VERSION 5.4 ;
NAMESCASESENSITIVE ON ;
BUSBITCHARS "[]" ;
DIVIDERCHAR "/" ;
UNITS
  DATABASE MICRONS 2000 ;
END UNITS
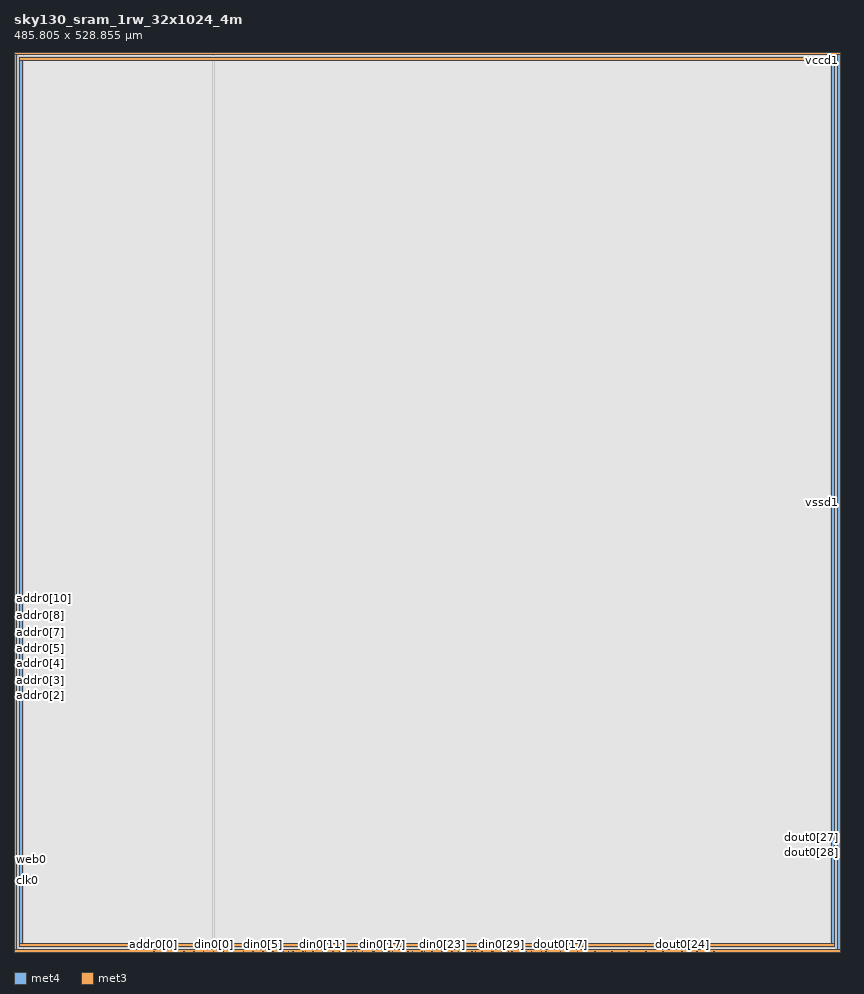
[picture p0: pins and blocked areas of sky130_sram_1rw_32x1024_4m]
MACRO sky130_sram_1rw_32x1024_4m
   CLASS BLOCK ;
   SIZE 485.805 BY 528.855 ;
   SYMMETRY X Y R90 ;
   PIN din0[0]
      DIRECTION INPUT ;
      PORT
         LAYER met4 ;
         RECT  117.08 0.0 117.46 0.38 ;
      END
   END din0[0]
   PIN din0[1]
      DIRECTION INPUT ;
      PORT
         LAYER met4 ;
         RECT  122.92 0.0 123.3 0.38 ;
      END
   END din0[1]
   PIN din0[2]
      DIRECTION INPUT ;
      PORT
         LAYER met4 ;
         RECT  128.76 0.0 129.14 0.38 ;
      END
   END din0[2]
   PIN din0[3]
      DIRECTION INPUT ;
      PORT
         LAYER met4 ;
         RECT  134.6 0.0 134.98 0.38 ;
      END
   END din0[3]
   PIN din0[4]
      DIRECTION INPUT ;
      PORT
         LAYER met4 ;
         RECT  140.44 0.0 140.82 0.38 ;
      END
   END din0[4]
   PIN din0[5]
      DIRECTION INPUT ;
      PORT
         LAYER met4 ;
         RECT  146.28 0.0 146.66 0.38 ;
      END
   END din0[5]
   PIN din0[6]
      DIRECTION INPUT ;
      PORT
         LAYER met4 ;
         RECT  152.12 0.0 152.5 0.38 ;
      END
   END din0[6]
   PIN din0[7]
      DIRECTION INPUT ;
      PORT
         LAYER met4 ;
         RECT  157.96 0.0 158.34 0.38 ;
      END
   END din0[7]
   PIN din0[8]
      DIRECTION INPUT ;
      PORT
         LAYER met4 ;
         RECT  163.8 0.0 164.18 0.38 ;
      END
   END din0[8]
   PIN din0[9]
      DIRECTION INPUT ;
      PORT
         LAYER met4 ;
         RECT  169.64 0.0 170.02 0.38 ;
      END
   END din0[9]
   PIN din0[10]
      DIRECTION INPUT ;
      PORT
         LAYER met4 ;
         RECT  175.48 0.0 175.86 0.38 ;
      END
   END din0[10]
   PIN din0[11]
      DIRECTION INPUT ;
      PORT
         LAYER met4 ;
         RECT  181.32 0.0 181.7 0.38 ;
      END
   END din0[11]
   PIN din0[12]
      DIRECTION INPUT ;
      PORT
         LAYER met4 ;
         RECT  187.16 0.0 187.54 0.38 ;
      END
   END din0[12]
   PIN din0[13]
      DIRECTION INPUT ;
      PORT
         LAYER met4 ;
         RECT  193.0 0.0 193.38 0.38 ;
      END
   END din0[13]
   PIN din0[14]
      DIRECTION INPUT ;
      PORT
         LAYER met4 ;
         RECT  198.84 0.0 199.22 0.38 ;
      END
   END din0[14]
   PIN din0[15]
      DIRECTION INPUT ;
      PORT
         LAYER met4 ;
         RECT  204.68 0.0 205.06 0.38 ;
      END
   END din0[15]
   PIN din0[16]
      DIRECTION INPUT ;
      PORT
         LAYER met4 ;
         RECT  210.52 0.0 210.9 0.38 ;
      END
   END din0[16]
   PIN din0[17]
      DIRECTION INPUT ;
      PORT
         LAYER met4 ;
         RECT  216.36 0.0 216.74 0.38 ;
      END
   END din0[17]
   PIN din0[18]
      DIRECTION INPUT ;
      PORT
         LAYER met4 ;
         RECT  222.2 0.0 222.58 0.38 ;
      END
   END din0[18]
   PIN din0[19]
      DIRECTION INPUT ;
      PORT
         LAYER met4 ;
         RECT  228.04 0.0 228.42 0.38 ;
      END
   END din0[19]
   PIN din0[20]
      DIRECTION INPUT ;
      PORT
         LAYER met4 ;
         RECT  233.88 0.0 234.26 0.38 ;
      END
   END din0[20]
   PIN din0[21]
      DIRECTION INPUT ;
      PORT
         LAYER met4 ;
         RECT  239.72 0.0 240.1 0.38 ;
      END
   END din0[21]
   PIN din0[22]
      DIRECTION INPUT ;
      PORT
         LAYER met4 ;
         RECT  245.56 0.0 245.94 0.38 ;
      END
   END din0[22]
   PIN din0[23]
      DIRECTION INPUT ;
      PORT
         LAYER met4 ;
         RECT  251.4 0.0 251.78 0.38 ;
      END
   END din0[23]
   PIN din0[24]
      DIRECTION INPUT ;
      PORT
         LAYER met4 ;
         RECT  257.24 0.0 257.62 0.38 ;
      END
   END din0[24]
   PIN din0[25]
      DIRECTION INPUT ;
      PORT
         LAYER met4 ;
         RECT  263.08 0.0 263.46 0.38 ;
      END
   END din0[25]
   PIN din0[26]
      DIRECTION INPUT ;
      PORT
         LAYER met4 ;
         RECT  268.92 0.0 269.3 0.38 ;
      END
   END din0[26]
   PIN din0[27]
      DIRECTION INPUT ;
      PORT
         LAYER met4 ;
         RECT  274.76 0.0 275.14 0.38 ;
      END
   END din0[27]
   PIN din0[28]
      DIRECTION INPUT ;
      PORT
         LAYER met4 ;
         RECT  280.6 0.0 280.98 0.38 ;
      END
   END din0[28]
   PIN din0[29]
      DIRECTION INPUT ;
      PORT
         LAYER met4 ;
         RECT  286.44 0.0 286.82 0.38 ;
      END
   END din0[29]
   PIN din0[30]
      DIRECTION INPUT ;
      PORT
         LAYER met4 ;
         RECT  292.28 0.0 292.66 0.38 ;
      END
   END din0[30]
   PIN din0[31]
      DIRECTION INPUT ;
      PORT
         LAYER met4 ;
         RECT  298.12 0.0 298.5 0.38 ;
      END
   END din0[31]
   PIN din0[32]
      DIRECTION INPUT ;
      PORT
         LAYER met4 ;
         RECT  303.96 0.0 304.34 0.38 ;
      END
   END din0[32]
   PIN addr0[0]
      DIRECTION INPUT ;
      PORT
         LAYER met4 ;
         RECT  82.04 0.0 82.42 0.38 ;
      END
   END addr0[0]
   PIN addr0[1]
      DIRECTION INPUT ;
      PORT
         LAYER met4 ;
         RECT  87.88 0.0 88.26 0.38 ;
      END
   END addr0[1]
   PIN addr0[2]
      DIRECTION INPUT ;
      PORT
         LAYER met3 ;
         RECT  0.0 150.77 0.38 151.15 ;
      END
   END addr0[2]
   PIN addr0[3]
      DIRECTION INPUT ;
      PORT
         LAYER met3 ;
         RECT  0.0 159.27 0.38 159.65 ;
      END
   END addr0[3]
   PIN addr0[4]
      DIRECTION INPUT ;
      PORT
         LAYER met3 ;
         RECT  0.0 164.91 0.38 165.29 ;
      END
   END addr0[4]
   PIN addr0[5]
      DIRECTION INPUT ;
      PORT
         LAYER met3 ;
         RECT  0.0 173.41 0.38 173.79 ;
      END
   END addr0[5]
   PIN addr0[6]
      DIRECTION INPUT ;
      PORT
         LAYER met3 ;
         RECT  0.0 179.05 0.38 179.43 ;
      END
   END addr0[6]
   PIN addr0[7]
      DIRECTION INPUT ;
      PORT
         LAYER met3 ;
         RECT  0.0 187.55 0.38 187.93 ;
      END
   END addr0[7]
   PIN addr0[8]
      DIRECTION INPUT ;
      PORT
         LAYER met3 ;
         RECT  0.0 193.19 0.38 193.57 ;
      END
   END addr0[8]
   PIN addr0[9]
      DIRECTION INPUT ;
      PORT
         LAYER met3 ;
         RECT  0.0 201.69 0.38 202.07 ;
      END
   END addr0[9]
   PIN addr0[10]
      DIRECTION INPUT ;
      PORT
         LAYER met3 ;
         RECT  0.0 207.33 0.38 207.71 ;
      END
   END addr0[10]
   PIN csb0
      DIRECTION INPUT ;
      PORT
         LAYER met3 ;
         RECT  0.0 41.11 0.38 41.49 ;
      END
   END csb0
   PIN web0
      DIRECTION INPUT ;
      PORT
         LAYER met3 ;
         RECT  0.0 49.61 0.38 49.99 ;
      END
   END web0
   PIN clk0
      DIRECTION INPUT ;
      PORT
         LAYER met3 ;
         RECT  0.0 41.855 0.38 42.235 ;
      END
   END clk0
   PIN wmask0[0]
      DIRECTION INPUT ;
      PORT
         LAYER met4 ;
         RECT  93.72 0.0 94.1 0.38 ;
      END
   END wmask0[0]
   PIN wmask0[1]
      DIRECTION INPUT ;
      PORT
         LAYER met4 ;
         RECT  99.56 0.0 99.94 0.38 ;
      END
   END wmask0[1]
   PIN wmask0[2]
      DIRECTION INPUT ;
      PORT
         LAYER met4 ;
         RECT  105.4 0.0 105.78 0.38 ;
      END
   END wmask0[2]
   PIN wmask0[3]
      DIRECTION INPUT ;
      PORT
         LAYER met4 ;
         RECT  111.24 0.0 111.62 0.38 ;
      END
   END wmask0[3]
   PIN spare_wen0
      DIRECTION INPUT ;
      PORT
         LAYER met4 ;
         RECT  309.8 0.0 310.18 0.38 ;
      END
   END spare_wen0
   PIN dout0[0]
      DIRECTION OUTPUT ;
      PORT
         LAYER met4 ;
         RECT  149.765 0.0 150.145 0.38 ;
      END
   END dout0[0]
   PIN dout0[1]
      DIRECTION OUTPUT ;
      PORT
         LAYER met4 ;
         RECT  161.03 0.0 161.41 0.38 ;
      END
   END dout0[1]
   PIN dout0[2]
      DIRECTION OUTPUT ;
      PORT
         LAYER met4 ;
         RECT  171.03 0.0 171.41 0.38 ;
      END
   END dout0[2]
   PIN dout0[3]
      DIRECTION OUTPUT ;
      PORT
         LAYER met4 ;
         RECT  182.41 0.0 182.79 0.38 ;
      END
   END dout0[3]
   PIN dout0[4]
      DIRECTION OUTPUT ;
      PORT
         LAYER met4 ;
         RECT  191.03 0.0 191.41 0.38 ;
      END
   END dout0[4]
   PIN dout0[5]
      DIRECTION OUTPUT ;
      PORT
         LAYER met4 ;
         RECT  201.03 0.0 201.41 0.38 ;
      END
   END dout0[5]
   PIN dout0[6]
      DIRECTION OUTPUT ;
      PORT
         LAYER met4 ;
         RECT  211.21 0.0 211.59 0.38 ;
      END
   END dout0[6]
   PIN dout0[7]
      DIRECTION OUTPUT ;
      PORT
         LAYER met4 ;
         RECT  220.345 0.0 220.725 0.38 ;
      END
   END dout0[7]
   PIN dout0[8]
      DIRECTION OUTPUT ;
      PORT
         LAYER met4 ;
         RECT  231.285 0.0 231.665 0.38 ;
      END
   END dout0[8]
   PIN dout0[9]
      DIRECTION OUTPUT ;
      PORT
         LAYER met4 ;
         RECT  241.03 0.0 241.41 0.38 ;
      END
   END dout0[9]
   PIN dout0[10]
      DIRECTION OUTPUT ;
      PORT
         LAYER met4 ;
         RECT  252.41 0.0 252.79 0.38 ;
      END
   END dout0[10]
   PIN dout0[11]
      DIRECTION OUTPUT ;
      PORT
         LAYER met4 ;
         RECT  261.03 0.0 261.41 0.38 ;
      END
   END dout0[11]
   PIN dout0[12]
      DIRECTION OUTPUT ;
      PORT
         LAYER met4 ;
         RECT  271.03 0.0 271.41 0.38 ;
      END
   END dout0[12]
   PIN dout0[13]
      DIRECTION OUTPUT ;
      PORT
         LAYER met4 ;
         RECT  281.29 0.0 281.67 0.38 ;
      END
   END dout0[13]
   PIN dout0[14]
      DIRECTION OUTPUT ;
      PORT
         LAYER met4 ;
         RECT  290.345 0.0 290.725 0.38 ;
      END
   END dout0[14]
   PIN dout0[15]
      DIRECTION OUTPUT ;
      PORT
         LAYER met4 ;
         RECT  301.03 0.0 301.41 0.38 ;
      END
   END dout0[15]
   PIN dout0[16]
      DIRECTION OUTPUT ;
      PORT
         LAYER met4 ;
         RECT  312.41 0.0 312.79 0.38 ;
      END
   END dout0[16]
   PIN dout0[17]
      DIRECTION OUTPUT ;
      PORT
         LAYER met4 ;
         RECT  321.03 0.0 321.41 0.38 ;
      END
   END dout0[17]
   PIN dout0[18]
      DIRECTION OUTPUT ;
      PORT
         LAYER met4 ;
         RECT  331.03 0.0 331.41 0.38 ;
      END
   END dout0[18]
   PIN dout0[19]
      DIRECTION OUTPUT ;
      PORT
         LAYER met4 ;
         RECT  341.03 0.0 341.41 0.38 ;
      END
   END dout0[19]
   PIN dout0[20]
      DIRECTION OUTPUT ;
      PORT
         LAYER met4 ;
         RECT  351.03 0.0 351.41 0.38 ;
      END
   END dout0[20]
   PIN dout0[21]
      DIRECTION OUTPUT ;
      PORT
         LAYER met4 ;
         RECT  361.03 0.0 361.41 0.38 ;
      END
   END dout0[21]
   PIN dout0[22]
      DIRECTION OUTPUT ;
      PORT
         LAYER met4 ;
         RECT  371.03 0.0 371.41 0.38 ;
      END
   END dout0[22]
   PIN dout0[23]
      DIRECTION OUTPUT ;
      PORT
         LAYER met4 ;
         RECT  381.03 0.0 381.41 0.38 ;
      END
   END dout0[23]
   PIN dout0[24]
      DIRECTION OUTPUT ;
      PORT
         LAYER met4 ;
         RECT  392.41 0.0 392.79 0.38 ;
      END
   END dout0[24]
   PIN dout0[25]
      DIRECTION OUTPUT ;
      PORT
         LAYER met4 ;
         RECT  401.03 0.0 401.41 0.38 ;
      END
   END dout0[25]
   PIN dout0[26]
      DIRECTION OUTPUT ;
      PORT
         LAYER met4 ;
         RECT  411.03 0.0 411.41 0.38 ;
      END
   END dout0[26]
   PIN dout0[27]
      DIRECTION OUTPUT ;
      PORT
         LAYER met3 ;
         RECT  485.425 67.11 485.805 67.49 ;
      END
   END dout0[27]
   PIN dout0[28]
      DIRECTION OUTPUT ;
      PORT
         LAYER met3 ;
         RECT  485.425 62.63 485.805 63.01 ;
      END
   END dout0[28]
   PIN dout0[29]
      DIRECTION OUTPUT ;
      PORT
         LAYER met3 ;
         RECT  485.425 63.32 485.805 63.7 ;
      END
   END dout0[29]
   PIN dout0[30]
      DIRECTION OUTPUT ;
      PORT
         LAYER met3 ;
         RECT  485.425 64.01 485.805 64.39 ;
      END
   END dout0[30]
   PIN dout0[31]
      DIRECTION OUTPUT ;
      PORT
         LAYER met3 ;
         RECT  485.425 65.5 485.805 65.88 ;
      END
   END dout0[31]
   PIN dout0[32]
      DIRECTION OUTPUT ;
      PORT
         LAYER met3 ;
         RECT  485.425 64.755 485.805 65.135 ;
      END
   END dout0[32]
   PIN vccd1
      DIRECTION INOUT ;
      USE POWER ; 
      SHAPE ABUTMENT ; 
      PORT
         LAYER met4 ;
         RECT  0.0 0.0 1.74 528.855 ;
         LAYER met3 ;
         RECT  0.0 527.115 485.805 528.855 ;
         LAYER met4 ;
         RECT  484.065 0.0 485.805 528.855 ;
         LAYER met3 ;
         RECT  0.0 0.0 485.805 1.74 ;
      END
   END vccd1
   PIN vssd1
      DIRECTION INOUT ;
      USE GROUND ; 
      SHAPE ABUTMENT ; 
      PORT
         LAYER met4 ;
         RECT  480.585 3.48 482.325 525.375 ;
         LAYER met3 ;
         RECT  3.48 3.48 482.325 5.22 ;
         LAYER met3 ;
         RECT  3.48 523.635 482.325 525.375 ;
         LAYER met4 ;
         RECT  3.48 3.48 5.22 525.375 ;
      END
   END vssd1
   OBS
   LAYER  met1 ;
      RECT  0.62 0.62 485.185 528.235 ;
   LAYER  met2 ;
      RECT  0.62 0.62 485.185 528.235 ;
   LAYER  met3 ;
      RECT  0.98 150.17 485.185 151.75 ;
      RECT  0.62 151.75 0.98 158.67 ;
      RECT  0.62 160.25 0.98 164.31 ;
      RECT  0.62 165.89 0.98 172.81 ;
      RECT  0.62 174.39 0.98 178.45 ;
      RECT  0.62 180.03 0.98 186.95 ;
      RECT  0.62 188.53 0.98 192.59 ;
      RECT  0.62 194.17 0.98 201.09 ;
      RECT  0.62 202.67 0.98 206.73 ;
      RECT  0.62 50.59 0.98 150.17 ;
      RECT  0.62 42.835 0.98 49.01 ;
      RECT  0.98 66.51 484.825 68.09 ;
      RECT  0.98 68.09 484.825 150.17 ;
      RECT  484.825 68.09 485.185 150.17 ;
      RECT  484.825 66.48 485.185 66.51 ;
      RECT  0.62 208.31 0.98 526.515 ;
      RECT  0.62 2.34 0.98 40.51 ;
      RECT  484.825 2.34 485.185 62.03 ;
      RECT  0.98 2.34 2.88 2.88 ;
      RECT  0.98 2.88 2.88 5.82 ;
      RECT  0.98 5.82 2.88 66.51 ;
      RECT  2.88 2.34 482.925 2.88 ;
      RECT  2.88 5.82 482.925 66.51 ;
      RECT  482.925 2.34 484.825 2.88 ;
      RECT  482.925 2.88 484.825 5.82 ;
      RECT  482.925 5.82 484.825 66.51 ;
      RECT  0.98 151.75 2.88 523.035 ;
      RECT  0.98 523.035 2.88 525.975 ;
      RECT  0.98 525.975 2.88 526.515 ;
      RECT  2.88 151.75 482.925 523.035 ;
      RECT  2.88 525.975 482.925 526.515 ;
      RECT  482.925 151.75 485.185 523.035 ;
      RECT  482.925 523.035 485.185 525.975 ;
      RECT  482.925 525.975 485.185 526.515 ;
   LAYER  met4 ;
      RECT  116.48 0.98 118.06 528.235 ;
      RECT  118.06 0.62 122.32 0.98 ;
      RECT  123.9 0.62 128.16 0.98 ;
      RECT  129.74 0.62 134.0 0.98 ;
      RECT  135.58 0.62 139.84 0.98 ;
      RECT  141.42 0.62 145.68 0.98 ;
      RECT  153.1 0.62 157.36 0.98 ;
      RECT  164.78 0.62 169.04 0.98 ;
      RECT  176.46 0.62 180.72 0.98 ;
      RECT  193.98 0.62 198.24 0.98 ;
      RECT  205.66 0.62 209.92 0.98 ;
      RECT  223.18 0.62 227.44 0.98 ;
      RECT  234.86 0.62 239.12 0.98 ;
      RECT  246.54 0.62 250.8 0.98 ;
      RECT  264.06 0.62 268.32 0.98 ;
      RECT  275.74 0.62 280.0 0.98 ;
      RECT  293.26 0.62 297.52 0.98 ;
      RECT  83.02 0.62 87.28 0.98 ;
      RECT  88.86 0.62 93.12 0.98 ;
      RECT  94.7 0.62 98.96 0.98 ;
      RECT  100.54 0.62 104.8 0.98 ;
      RECT  106.38 0.62 110.64 0.98 ;
      RECT  112.22 0.62 116.48 0.98 ;
      RECT  304.94 0.62 309.2 0.98 ;
      RECT  147.26 0.62 149.165 0.98 ;
      RECT  150.745 0.62 151.52 0.98 ;
      RECT  158.94 0.62 160.43 0.98 ;
      RECT  162.01 0.62 163.2 0.98 ;
      RECT  172.01 0.62 174.88 0.98 ;
      RECT  183.39 0.62 186.56 0.98 ;
      RECT  188.14 0.62 190.43 0.98 ;
      RECT  192.01 0.62 192.4 0.98 ;
      RECT  199.82 0.62 200.43 0.98 ;
      RECT  202.01 0.62 204.08 0.98 ;
      RECT  212.19 0.62 215.76 0.98 ;
      RECT  217.34 0.62 219.745 0.98 ;
      RECT  221.325 0.62 221.6 0.98 ;
      RECT  229.02 0.62 230.685 0.98 ;
      RECT  232.265 0.62 233.28 0.98 ;
      RECT  242.01 0.62 244.96 0.98 ;
      RECT  253.39 0.62 256.64 0.98 ;
      RECT  258.22 0.62 260.43 0.98 ;
      RECT  262.01 0.62 262.48 0.98 ;
      RECT  269.9 0.62 270.43 0.98 ;
      RECT  272.01 0.62 274.16 0.98 ;
      RECT  282.27 0.62 285.84 0.98 ;
      RECT  287.42 0.62 289.745 0.98 ;
      RECT  291.325 0.62 291.68 0.98 ;
      RECT  299.1 0.62 300.43 0.98 ;
      RECT  302.01 0.62 303.36 0.98 ;
      RECT  310.78 0.62 311.81 0.98 ;
      RECT  313.39 0.62 320.43 0.98 ;
      RECT  322.01 0.62 330.43 0.98 ;
      RECT  332.01 0.62 340.43 0.98 ;
      RECT  342.01 0.62 350.43 0.98 ;
      RECT  352.01 0.62 360.43 0.98 ;
      RECT  362.01 0.62 370.43 0.98 ;
      RECT  372.01 0.62 380.43 0.98 ;
      RECT  382.01 0.62 391.81 0.98 ;
      RECT  393.39 0.62 400.43 0.98 ;
      RECT  402.01 0.62 410.43 0.98 ;
      RECT  2.34 0.62 81.44 0.98 ;
      RECT  412.01 0.62 483.465 0.98 ;
      RECT  118.06 0.98 479.985 2.88 ;
      RECT  118.06 2.88 479.985 525.975 ;
      RECT  118.06 525.975 479.985 528.235 ;
      RECT  479.985 0.98 482.925 2.88 ;
      RECT  479.985 525.975 482.925 528.235 ;
      RECT  482.925 0.98 483.465 2.88 ;
      RECT  482.925 2.88 483.465 525.975 ;
      RECT  482.925 525.975 483.465 528.235 ;
      RECT  2.34 0.98 2.88 2.88 ;
      RECT  2.34 2.88 2.88 525.975 ;
      RECT  2.34 525.975 2.88 528.235 ;
      RECT  2.88 0.98 5.82 2.88 ;
      RECT  2.88 525.975 5.82 528.235 ;
      RECT  5.82 0.98 116.48 2.88 ;
      RECT  5.82 2.88 116.48 525.975 ;
      RECT  5.82 525.975 116.48 528.235 ;
   END
END    sky130_sram_1rw_32x1024_4m
END    LIBRARY
